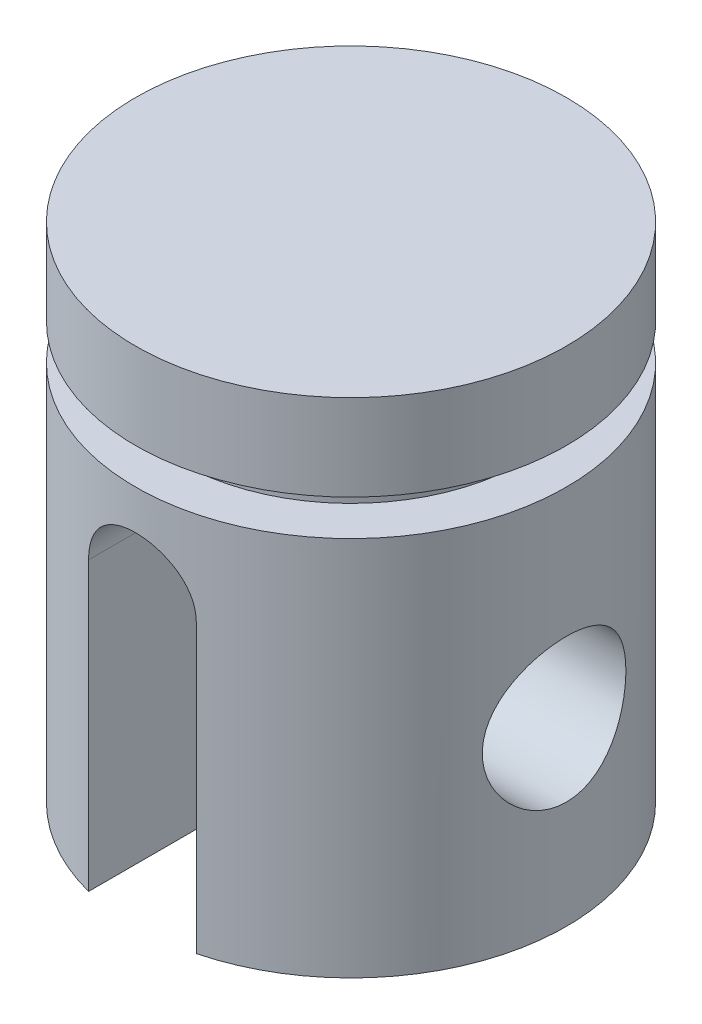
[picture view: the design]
ISO-10303-21;
HEADER;
FILE_DESCRIPTION(('STEP AP214'),'2;1');
FILE_NAME('part.step','',(''),(''),'','','');
FILE_SCHEMA(('AUTOMOTIVE_DESIGN { 1 0 10303 214 1 1 1 1 }'));
ENDSEC;
DATA;
#1=APPLICATION_CONTEXT('core data for automotive mechanical design processes');
#2=APPLICATION_PROTOCOL_DEFINITION('international standard','automotive_design',2000,#1);
#3=PRODUCT_CONTEXT('',#1,'mechanical');
#4=PRODUCT('Part','Part','',(#3));
#5=PRODUCT_RELATED_PRODUCT_CATEGORY('part','',(#4));
#6=PRODUCT_DEFINITION_FORMATION('','',#4);
#7=PRODUCT_DEFINITION_CONTEXT('part definition',#1,'design');
#8=PRODUCT_DEFINITION('design','',#6,#7);
#9=PRODUCT_DEFINITION_SHAPE('','',#8);
#10=(LENGTH_UNIT() NAMED_UNIT(*) SI_UNIT(.MILLI.,.METRE.));
#11=(NAMED_UNIT(*) PLANE_ANGLE_UNIT() SI_UNIT($,.RADIAN.));
#12=(NAMED_UNIT(*) SI_UNIT($,.STERADIAN.) SOLID_ANGLE_UNIT());
#13=UNCERTAINTY_MEASURE_WITH_UNIT(LENGTH_MEASURE(1.E-05),#10,'distance_accuracy_value','');
#14=(GEOMETRIC_REPRESENTATION_CONTEXT(3) GLOBAL_UNCERTAINTY_ASSIGNED_CONTEXT((#13)) GLOBAL_UNIT_ASSIGNED_CONTEXT((#10,
#11,#12)) REPRESENTATION_CONTEXT('',''));
#15=CARTESIAN_POINT('',(0.,0.,0.));
#16=DIRECTION('',(0.,0.,1.));
#17=DIRECTION('',(1.,0.,0.));
#18=AXIS2_PLACEMENT_3D('',#15,#16,#17);
#19=CARTESIAN_POINT('',(30.,0.,0.));
#20=DIRECTION('',(0.,-1.,0.));
#21=DIRECTION('',(0.,0.,-1.));
#22=AXIS2_PLACEMENT_3D('',#19,#20,#21);
#23=PLANE('',#22);
#24=DIRECTION('',(0.,0.,1.));
#25=VECTOR('',#24,1.);
#26=CARTESIAN_POINT('',(-7.5,0.,-30.));
#27=LINE('',#26,#25);
#28=CARTESIAN_POINT('',(-7.5,0.,-29.0473750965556));
#29=VERTEX_POINT('',#28);
#30=CARTESIAN_POINT('',(-7.5,0.,29.0473750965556));
#31=VERTEX_POINT('',#30);
#32=EDGE_CURVE('E110',#29,#31,#27,.T.);
#33=ORIENTED_EDGE('',*,*,#32,.T.);
#34=CARTESIAN_POINT('',(0.,0.,0.));
#35=DIRECTION('',(0.,-1.,0.));
#36=DIRECTION('',(0.,0.,-1.));
#37=AXIS2_PLACEMENT_3D('',#34,#35,#36);
#38=CIRCLE('',#37,30.);
#39=EDGE_CURVE('E117',#31,#29,#38,.T.);
#40=ORIENTED_EDGE('',*,*,#39,.T.);
#41=EDGE_LOOP('',(#33,#40));
#42=FACE_BOUND('',#41,.T.);
#43=ADVANCED_FACE('F40',(#42),#23,.T.);
#44=DIRECTION('',(0.,0.,1.));
#45=VECTOR('',#44,1.);
#46=CARTESIAN_POINT('',(7.5,0.,-30.));
#47=LINE('',#46,#45);
#48=CARTESIAN_POINT('',(7.5,0.,-29.0473750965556));
#49=VERTEX_POINT('',#48);
#50=CARTESIAN_POINT('',(7.5,0.,29.0473750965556));
#51=VERTEX_POINT('',#50);
#52=EDGE_CURVE('E98',#49,#51,#47,.T.);
#53=ORIENTED_EDGE('',*,*,#52,.F.);
#54=EDGE_CURVE('E121',#49,#51,#38,.T.);
#55=ORIENTED_EDGE('',*,*,#54,.T.);
#56=EDGE_LOOP('',(#53,#55));
#57=FACE_BOUND('',#56,.T.);
#58=ADVANCED_FACE('F42',(#57),#23,.T.);
#59=CARTESIAN_POINT('',(0.,70.,0.));
#60=DIRECTION('',(0.,1.,0.));
#61=DIRECTION('',(0.,0.,1.));
#62=AXIS2_PLACEMENT_3D('',#59,#60,#61);
#63=PLANE('',#62);
#64=CARTESIAN_POINT('',(0.,70.,0.));
#65=DIRECTION('',(0.,-1.,0.));
#66=DIRECTION('',(0.,0.,-1.));
#67=AXIS2_PLACEMENT_3D('',#64,#65,#66);
#68=CIRCLE('',#67,30.);
#69=CARTESIAN_POINT('',(0.,70.,-30.));
#70=VERTEX_POINT('',#69);
#71=EDGE_CURVE('E94',#70,#70,#68,.T.);
#72=ORIENTED_EDGE('',*,*,#71,.F.);
#73=EDGE_LOOP('',(#72));
#74=FACE_BOUND('',#73,.T.);
#75=ADVANCED_FACE('F207',(#74),#63,.T.);
#76=CARTESIAN_POINT('',(0.,70.,0.));
#77=DIRECTION('',(0.,-1.,0.));
#78=DIRECTION('',(0.,0.,-1.));
#79=AXIS2_PLACEMENT_3D('',#76,#77,#78);
#80=CYLINDRICAL_SURFACE('',#79,30.);
#81=ORIENTED_EDGE('',*,*,#71,.T.);
#82=EDGE_LOOP('',(#81));
#83=FACE_BOUND('',#82,.T.);
#84=CARTESIAN_POINT('',(0.,58.,0.));
#85=DIRECTION('',(0.,-1.,0.));
#86=DIRECTION('',(0.,0.,-1.));
#87=AXIS2_PLACEMENT_3D('',#84,#85,#86);
#88=CIRCLE('',#87,30.);
#89=CARTESIAN_POINT('',(0.,58.,-30.));
#90=VERTEX_POINT('',#89);
#91=EDGE_CURVE('E134',#90,#90,#88,.T.);
#92=ORIENTED_EDGE('',*,*,#91,.F.);
#93=EDGE_LOOP('',(#92));
#94=FACE_BOUND('',#93,.T.);
#95=ADVANCED_FACE('F235',(#83,#94),#80,.T.);
#96=CARTESIAN_POINT('',(30.,58.,0.));
#97=DIRECTION('',(0.,-1.,0.));
#98=DIRECTION('',(0.,0.,-1.));
#99=AXIS2_PLACEMENT_3D('',#96,#97,#98);
#100=PLANE('',#99);
#101=ORIENTED_EDGE('',*,*,#91,.T.);
#102=EDGE_LOOP('',(#101));
#103=FACE_BOUND('',#102,.T.);
#104=CARTESIAN_POINT('',(0.,58.,0.));
#105=DIRECTION('',(0.,-1.,0.));
#106=DIRECTION('',(0.,0.,-1.));
#107=AXIS2_PLACEMENT_3D('',#104,#105,#106);
#108=CIRCLE('',#107,24.);
#109=CARTESIAN_POINT('',(0.,58.,-24.));
#110=VERTEX_POINT('',#109);
#111=EDGE_CURVE('E130',#110,#110,#108,.T.);
#112=ORIENTED_EDGE('',*,*,#111,.F.);
#113=EDGE_LOOP('',(#112));
#114=FACE_BOUND('',#113,.T.);
#115=ADVANCED_FACE('F228',(#103,#114),#100,.T.);
#116=CARTESIAN_POINT('',(0.,70.,0.));
#117=DIRECTION('',(0.,-1.,0.));
#118=DIRECTION('',(0.,0.,-1.));
#119=AXIS2_PLACEMENT_3D('',#116,#117,#118);
#120=CYLINDRICAL_SURFACE('',#119,24.);
#121=ORIENTED_EDGE('',*,*,#111,.T.);
#122=EDGE_LOOP('',(#121));
#123=FACE_BOUND('',#122,.T.);
#124=CARTESIAN_POINT('',(0.,53.,0.));
#125=DIRECTION('',(0.,-1.,0.));
#126=DIRECTION('',(0.,0.,-1.));
#127=AXIS2_PLACEMENT_3D('',#124,#125,#126);
#128=CIRCLE('',#127,24.);
#129=CARTESIAN_POINT('',(0.,53.,-24.));
#130=VERTEX_POINT('',#129);
#131=EDGE_CURVE('E126',#130,#130,#128,.T.);
#132=ORIENTED_EDGE('',*,*,#131,.F.);
#133=EDGE_LOOP('',(#132));
#134=FACE_BOUND('',#133,.T.);
#135=ADVANCED_FACE('F220',(#123,#134),#120,.T.);
#136=CARTESIAN_POINT('',(24.,53.,0.));
#137=DIRECTION('',(0.,1.,0.));
#138=DIRECTION('',(0.,0.,1.));
#139=AXIS2_PLACEMENT_3D('',#136,#137,#138);
#140=PLANE('',#139);
#141=ORIENTED_EDGE('',*,*,#131,.T.);
#142=EDGE_LOOP('',(#141));
#143=FACE_BOUND('',#142,.T.);
#144=CARTESIAN_POINT('',(0.,53.,0.));
#145=DIRECTION('',(0.,-1.,0.));
#146=DIRECTION('',(0.,0.,-1.));
#147=AXIS2_PLACEMENT_3D('',#144,#145,#146);
#148=CIRCLE('',#147,30.);
#149=CARTESIAN_POINT('',(0.,53.,-30.));
#150=VERTEX_POINT('',#149);
#151=EDGE_CURVE('E122',#150,#150,#148,.T.);
#152=ORIENTED_EDGE('',*,*,#151,.F.);
#153=EDGE_LOOP('',(#152));
#154=FACE_BOUND('',#153,.T.);
#155=ADVANCED_FACE('F213',(#143,#154),#140,.T.);
#156=CARTESIAN_POINT('',(0.,70.,0.));
#157=DIRECTION('',(0.,-1.,0.));
#158=DIRECTION('',(0.,0.,-1.));
#159=AXIS2_PLACEMENT_3D('',#156,#157,#158);
#160=CYLINDRICAL_SURFACE('',#159,30.);
#161=CARTESIAN_POINT('',(-30.,15.,0.));
#162=CARTESIAN_POINT('',(-30.0000000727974,14.9999998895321,0.272817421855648));
#163=CARTESIAN_POINT('',(-29.9962700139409,15.0111733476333,0.545633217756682));
#164=CARTESIAN_POINT('',(-29.9814525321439,15.0557586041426,1.08923625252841));
#165=CARTESIAN_POINT('',(-29.9703651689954,15.0891702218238,1.36002350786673));
#166=CARTESIAN_POINT('',(-29.9411347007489,15.1779177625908,1.89761112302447));
#167=CARTESIAN_POINT('',(-29.922991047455,15.2332553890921,2.16441117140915));
#168=CARTESIAN_POINT('',(-29.8801375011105,15.3653481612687,2.69211184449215));
#169=CARTESIAN_POINT('',(-29.8554275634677,15.4421034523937,2.95301242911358));
#170=CARTESIAN_POINT('',(-29.8001502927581,15.6161973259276,3.46664728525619));
#171=CARTESIAN_POINT('',(-29.769594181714,15.7134965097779,3.71939613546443));
#172=CARTESIAN_POINT('',(-29.7033758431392,15.9280132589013,4.21570540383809));
#173=CARTESIAN_POINT('',(-29.6677117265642,16.0452381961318,4.45926238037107));
#174=CARTESIAN_POINT('',(-29.5921987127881,16.2986867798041,4.93557741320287));
#175=CARTESIAN_POINT('',(-29.5523500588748,16.4349093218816,5.16833609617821));
#176=CARTESIAN_POINT('',(-29.4694667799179,16.7254094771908,5.62171195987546));
#177=CARTESIAN_POINT('',(-29.4264319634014,16.8796881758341,5.84232840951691));
#178=CARTESIAN_POINT('',(-29.3368734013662,17.2103752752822,6.27682953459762));
#179=CARTESIAN_POINT('',(-29.2902826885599,17.3873240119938,6.49028930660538));
#180=CARTESIAN_POINT('',(-29.1960870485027,17.7582003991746,6.90166928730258));
#181=CARTESIAN_POINT('',(-29.1484821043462,17.9521283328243,7.09958923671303));
#182=CARTESIAN_POINT('',(-29.0535150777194,18.355812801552,7.47873453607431));
#183=CARTESIAN_POINT('',(-29.0061530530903,18.5655729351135,7.65995606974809));
#184=CARTESIAN_POINT('',(-28.9129673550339,18.9996166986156,8.00450980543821));
#185=CARTESIAN_POINT('',(-28.8671436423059,19.2238999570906,8.16784246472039));
#186=CARTESIAN_POINT('',(-28.7770145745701,19.692372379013,8.48001162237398));
#187=CARTESIAN_POINT('',(-28.7327920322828,19.9369505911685,8.62828897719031));
#188=CARTESIAN_POINT('',(-28.6486860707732,20.438392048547,8.90356690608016));
#189=CARTESIAN_POINT('',(-28.6088009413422,20.6952503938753,9.0305758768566));
#190=CARTESIAN_POINT('',(-28.534611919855,21.2196006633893,9.26232893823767));
#191=CARTESIAN_POINT('',(-28.5003078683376,21.4870922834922,9.36707366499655));
#192=CARTESIAN_POINT('',(-28.4384115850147,22.0307959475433,9.55334459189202));
#193=CARTESIAN_POINT('',(-28.4108190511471,22.307007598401,9.63487183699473));
#194=CARTESIAN_POINT('',(-28.3640896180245,22.8566360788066,9.77156399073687));
#195=CARTESIAN_POINT('',(-28.3446991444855,23.1298335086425,9.82752458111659));
#196=CARTESIAN_POINT('',(-28.3137046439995,23.680382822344,9.91646893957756));
#197=CARTESIAN_POINT('',(-28.3021004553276,23.957734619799,9.94945318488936));
#198=CARTESIAN_POINT('',(-28.2870721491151,24.5143726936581,9.992100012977));
#199=CARTESIAN_POINT('',(-28.2836458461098,24.7936584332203,10.001768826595));
#200=CARTESIAN_POINT('',(-28.2850842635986,25.3520337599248,9.99770051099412));
#201=CARTESIAN_POINT('',(-28.2899487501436,25.6311233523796,9.98396404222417));
#202=CARTESIAN_POINT('',(-28.307391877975,26.1741814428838,9.93439524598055));
#203=CARTESIAN_POINT('',(-28.319607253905,26.4382573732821,9.89960301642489));
#204=CARTESIAN_POINT('',(-28.3510582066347,26.9623784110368,9.80916853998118));
#205=CARTESIAN_POINT('',(-28.3702935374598,27.222423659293,9.75352702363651));
#206=CARTESIAN_POINT('',(-28.4152063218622,27.7367087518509,9.62189570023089));
#207=CARTESIAN_POINT('',(-28.4408831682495,27.990949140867,9.54590781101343));
#208=CARTESIAN_POINT('',(-28.4979443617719,28.4921119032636,9.37418519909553));
#209=CARTESIAN_POINT('',(-28.529330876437,28.7390314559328,9.27844297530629));
#210=CARTESIAN_POINT('',(-28.5974561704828,29.227762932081,9.0663166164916));
#211=CARTESIAN_POINT('',(-28.6342713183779,29.4694335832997,8.94963170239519));
#212=CARTESIAN_POINT('',(-28.7118622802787,29.9422102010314,8.69749161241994));
#213=CARTESIAN_POINT('',(-28.7526394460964,30.1733125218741,8.56203002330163));
#214=CARTESIAN_POINT('',(-28.8370515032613,30.6235621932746,8.27327503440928));
#215=CARTESIAN_POINT('',(-28.8806865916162,30.8427087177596,8.11998040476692));
#216=CARTESIAN_POINT('',(-28.9696785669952,31.2678135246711,7.79652835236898));
#217=CARTESIAN_POINT('',(-29.0150355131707,31.4737713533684,7.62637034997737));
#218=CARTESIAN_POINT('',(-29.1087179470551,31.8817825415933,7.26085153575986));
#219=CARTESIAN_POINT('',(-29.1570743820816,32.0830648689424,7.06463704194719));
#220=CARTESIAN_POINT('',(-29.2530762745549,32.4684195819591,6.65594240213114));
#221=CARTESIAN_POINT('',(-29.300721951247,32.6524973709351,6.44346740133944));
#222=CARTESIAN_POINT('',(-29.3940440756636,33.002391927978,6.00339730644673));
#223=CARTESIAN_POINT('',(-29.4397195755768,33.1681999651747,5.77579506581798));
#224=CARTESIAN_POINT('',(-29.5278149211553,33.4802271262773,5.30706897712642));
#225=CARTESIAN_POINT('',(-29.5702360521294,33.6264540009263,5.06595053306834));
#226=CARTESIAN_POINT('',(-29.6510879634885,33.8996756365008,4.56913058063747));
#227=CARTESIAN_POINT('',(-29.6894737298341,34.0264594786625,4.31330561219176));
#228=CARTESIAN_POINT('',(-29.7606637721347,34.2579286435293,3.79108523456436));
#229=CARTESIAN_POINT('',(-29.7934679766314,34.3626136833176,3.5246896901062));
#230=CARTESIAN_POINT('',(-29.8525359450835,34.5489114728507,2.98332200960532));
#231=CARTESIAN_POINT('',(-29.8788015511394,34.6305307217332,2.70835231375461));
#232=CARTESIAN_POINT('',(-29.92402797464,34.769943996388,2.15185145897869));
#233=CARTESIAN_POINT('',(-29.9429891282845,34.8277391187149,1.87032060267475));
#234=CARTESIAN_POINT('',(-29.9723879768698,34.9169416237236,1.31523069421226));
#235=CARTESIAN_POINT('',(-29.9831596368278,34.949384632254,1.04185537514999));
#236=CARTESIAN_POINT('',(-29.9972012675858,34.9916207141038,0.493170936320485));
#237=CARTESIAN_POINT('',(-30.0004714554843,35.0014144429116,0.217861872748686));
#238=CARTESIAN_POINT('',(-29.9994188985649,34.9982566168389,-0.332568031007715));
#239=CARTESIAN_POINT('',(-29.9950972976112,34.9853084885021,-0.607688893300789));
#240=CARTESIAN_POINT('',(-29.9789840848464,34.9368007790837,-1.15570622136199));
#241=CARTESIAN_POINT('',(-29.9671925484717,34.9012414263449,-1.4286027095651));
#242=CARTESIAN_POINT('',(-29.9369169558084,34.8092212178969,-1.96222703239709));
#243=CARTESIAN_POINT('',(-29.9186384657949,34.7534012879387,-2.22307746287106));
#244=CARTESIAN_POINT('',(-29.8758162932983,34.6212424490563,-2.7390974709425));
#245=CARTESIAN_POINT('',(-29.8512703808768,34.5448962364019,-2.99426499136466));
#246=CARTESIAN_POINT('',(-29.7965488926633,34.372353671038,-3.49708740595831));
#247=CARTESIAN_POINT('',(-29.7663749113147,34.2761629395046,-3.74474440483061));
#248=CARTESIAN_POINT('',(-29.7011345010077,34.0646297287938,-4.23117712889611));
#249=CARTESIAN_POINT('',(-29.6660661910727,33.949279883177,-4.46994939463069));
#250=CARTESIAN_POINT('',(-29.5909467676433,33.6970680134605,-4.94315066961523));
#251=CARTESIAN_POINT('',(-29.5507901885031,33.5597265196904,-5.17730735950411));
#252=CARTESIAN_POINT('',(-29.4672484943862,33.2667077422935,-5.63338688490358));
#253=CARTESIAN_POINT('',(-29.4238619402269,33.1110222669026,-5.85530418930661));
#254=CARTESIAN_POINT('',(-29.3349700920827,32.7823833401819,-6.28552190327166));
#255=CARTESIAN_POINT('',(-29.2894647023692,32.6094291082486,-6.49382169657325));
#256=CARTESIAN_POINT('',(-29.1974842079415,32.2473266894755,-6.89560723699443));
#257=CARTESIAN_POINT('',(-29.1510090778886,32.058178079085,-7.08909259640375));
#258=CARTESIAN_POINT('',(-29.0561491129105,31.6558052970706,-7.46861368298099));
#259=CARTESIAN_POINT('',(-29.007774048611,31.4418759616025,-7.65390507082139));
#260=CARTESIAN_POINT('',(-28.9126373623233,30.998946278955,-8.00578656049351));
#261=CARTESIAN_POINT('',(-28.865875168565,30.7699513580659,-8.17238333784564));
#262=CARTESIAN_POINT('',(-28.7752794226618,30.2981425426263,-8.48586679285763));
#263=CARTESIAN_POINT('',(-28.7314471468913,30.0553227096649,-8.63274490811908));
#264=CARTESIAN_POINT('',(-28.6480650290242,29.5576069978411,-8.90554413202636));
#265=CARTESIAN_POINT('',(-28.6085133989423,29.3027162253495,-9.03147400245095));
#266=CARTESIAN_POINT('',(-28.5349686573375,28.7829217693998,-9.26121465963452));
#267=CARTESIAN_POINT('',(-28.5009658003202,28.5180366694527,-9.3650643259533));
#268=CARTESIAN_POINT('',(-28.4395326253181,27.9796830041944,-9.54999948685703));
#269=CARTESIAN_POINT('',(-28.4121023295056,27.7062144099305,-9.63108490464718));
#270=CARTESIAN_POINT('',(-28.364744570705,27.1528332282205,-9.76967941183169));
#271=CARTESIAN_POINT('',(-28.3448142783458,26.8729231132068,-9.82719739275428));
#272=CARTESIAN_POINT('',(-28.3131339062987,26.3087576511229,-9.91810350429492));
#273=CARTESIAN_POINT('',(-28.301383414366,26.0245025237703,-9.95149285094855));
#274=CARTESIAN_POINT('',(-28.2868595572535,25.4686336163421,-9.99269827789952));
#275=CARTESIAN_POINT('',(-28.2836556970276,25.1971213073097,-10.0017409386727));
#276=CARTESIAN_POINT('',(-28.2850819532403,24.6542875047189,-9.99770707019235));
#277=CARTESIAN_POINT('',(-28.2897117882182,24.3829660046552,-9.98463133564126));
#278=CARTESIAN_POINT('',(-28.3066557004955,23.8425445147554,-9.9364928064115));
#279=CARTESIAN_POINT('',(-28.3189692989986,23.573444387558,-9.90143138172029));
#280=CARTESIAN_POINT('',(-28.3508886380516,23.0394036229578,-9.80966197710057));
#281=CARTESIAN_POINT('',(-28.3704944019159,22.7744629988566,-9.7529539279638));
#282=CARTESIAN_POINT('',(-28.4159458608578,22.2556454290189,-9.61971250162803));
#283=CARTESIAN_POINT('',(-28.441664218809,22.0016536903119,-9.54358162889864));
#284=CARTESIAN_POINT('',(-28.498791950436,21.5009969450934,-9.3716093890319));
#285=CARTESIAN_POINT('',(-28.5302033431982,21.2543345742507,-9.27576102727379));
#286=CARTESIAN_POINT('',(-28.597830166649,20.76993896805,-9.06511647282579));
#287=CARTESIAN_POINT('',(-28.6340454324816,20.5322054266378,-8.9503209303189));
#288=CARTESIAN_POINT('',(-28.7103060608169,20.0670154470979,-8.7025924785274));
#289=CARTESIAN_POINT('',(-28.7503516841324,19.839559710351,-8.56965833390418));
#290=CARTESIAN_POINT('',(-28.8350396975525,19.3865184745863,-8.28034879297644));
#291=CARTESIAN_POINT('',(-28.8798064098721,19.1614474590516,-8.12320375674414));
#292=CARTESIAN_POINT('',(-28.9711505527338,18.725203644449,-7.791153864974));
#293=CARTESIAN_POINT('',(-29.0177280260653,18.5140311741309,-7.61624858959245));
#294=CARTESIAN_POINT('',(-29.1114649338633,18.1067657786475,-7.24971676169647));
#295=CARTESIAN_POINT('',(-29.1586245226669,17.9106769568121,-7.0580856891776));
#296=CARTESIAN_POINT('',(-29.2522781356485,17.5348203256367,-6.65929199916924));
#297=CARTESIAN_POINT('',(-29.2987721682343,17.3550523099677,-6.45212957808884));
#298=CARTESIAN_POINT('',(-29.3916811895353,17.0062342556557,-6.01505765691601));
#299=CARTESIAN_POINT('',(-29.4380213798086,16.8378823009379,-5.78457436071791));
#300=CARTESIAN_POINT('',(-29.5273677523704,16.5212909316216,-5.30969823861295));
#301=CARTESIAN_POINT('',(-29.5703751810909,16.3730439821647,-5.06531067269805));
#302=CARTESIAN_POINT('',(-29.6518631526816,16.0977371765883,-4.56414864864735));
#303=CARTESIAN_POINT('',(-29.6903436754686,15.9706774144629,-4.30737413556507));
#304=CARTESIAN_POINT('',(-29.7616741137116,15.7388217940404,-3.78321180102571));
#305=CARTESIAN_POINT('',(-29.7945243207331,15.6340247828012,-3.51582453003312));
#306=CARTESIAN_POINT('',(-29.8523172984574,15.4518077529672,-2.98451649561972));
#307=CARTESIAN_POINT('',(-29.877547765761,15.3733738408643,-2.72097451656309));
#308=CARTESIAN_POINT('',(-29.9213145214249,15.238384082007,-2.1878001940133));
#309=CARTESIAN_POINT('',(-29.9398510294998,15.181827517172,-1.91816805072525));
#310=CARTESIAN_POINT('',(-29.9697157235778,15.0911304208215,-1.37482625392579));
#311=CARTESIAN_POINT('',(-29.9810455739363,15.0569847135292,-1.10111755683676));
#312=CARTESIAN_POINT('',(-29.9961876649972,15.0114195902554,-0.551605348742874));
#313=CARTESIAN_POINT('',(-29.9999999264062,15.0000001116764,-0.275801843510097));
#314=CARTESIAN_POINT('',(-30.,15.,0.));
#315=B_SPLINE_CURVE_WITH_KNOTS('',3,(#161,#162,#163,#164,#165,#166,#167,#168,#169,#170,#171,
#172,#173,#174,#175,#176,#177,#178,#179,#180,#181,#182,#183,#184,#185,#186,#187,#188,#189,#190,
#191,#192,#193,#194,#195,#196,#197,#198,#199,#200,#201,#202,#203,#204,#205,#206,#207,#208,#209,
#210,#211,#212,#213,#214,#215,#216,#217,#218,#219,#220,#221,#222,#223,#224,#225,#226,#227,#228,
#229,#230,#231,#232,#233,#234,#235,#236,#237,#238,#239,#240,#241,#242,#243,#244,#245,#246,#247,
#248,#249,#250,#251,#252,#253,#254,#255,#256,#257,#258,#259,#260,#261,#262,#263,#264,#265,#266,
#267,#268,#269,#270,#271,#272,#273,#274,#275,#276,#277,#278,#279,#280,#281,#282,#283,#284,#285,
#286,#287,#288,#289,#290,#291,#292,#293,#294,#295,#296,#297,#298,#299,#300,#301,#302,#303,#304,
#305,#306,#307,#308,#309,#310,#311,#312,#313,#314),.UNSPECIFIED.,.T.,.F.,(4,2,2,2,2,2,2,2,2,2,2,
2,2,2,2,2,2,2,2,2,2,2,2,2,2,2,2,2,2,2,2,2,2,2,2,2,2,2,2,2,2,2,2,2,2,2,2,2,2,2,2,2,2,2,2,2,2,2,2,
2,2,2,2,2,2,2,2,2,2,2,2,2,2,2,2,2,4),(0.,0.818196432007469,1.6363862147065,2.45463957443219,
3.2728984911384,4.08960219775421,4.90660872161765,5.72356777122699,6.54057595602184,
7.38307938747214,8.22559687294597,9.06830643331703,9.91099444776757,10.7781693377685,
11.645001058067,12.5118080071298,13.3785759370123,14.2161395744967,15.0536858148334,
15.8910082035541,16.7283069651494,17.5272827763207,18.3262305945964,19.1251031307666,
19.9242795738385,20.7360167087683,21.5480317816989,22.3601028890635,23.1722019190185,
24.0268844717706,24.881297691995,25.7361174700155,26.590597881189,27.453776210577,
28.3169655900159,29.1799115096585,30.0428177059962,30.8683037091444,31.6937658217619,
32.5191035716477,33.3444329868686,34.1456526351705,34.9471577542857,35.7484361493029,
36.5500233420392,37.3723552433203,38.1950557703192,39.0177935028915,39.8405527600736,
40.7009055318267,41.5609501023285,42.4213669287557,43.2814229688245,44.1399518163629,
44.998483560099,45.8566910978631,46.7148553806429,47.5288973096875,48.3429099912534,
49.1568719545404,49.9708365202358,50.7691377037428,51.5677225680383,52.3662800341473,
53.1648919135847,53.9983437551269,54.831815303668,55.665512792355,56.4991997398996,
57.3656243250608,58.2317232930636,59.0978261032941,59.9638840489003,60.7912515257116,
61.618591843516,62.4457410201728,63.2728879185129),.UNSPECIFIED.);
#316=CARTESIAN_POINT('',(-30.,15.,0.));
#317=VERTEX_POINT('',#316);
#318=EDGE_CURVE('E113',#317,#317,#315,.T.);
#319=ORIENTED_EDGE('',*,*,#318,.F.);
#320=EDGE_LOOP('',(#319));
#321=FACE_BOUND('',#320,.T.);
#322=CARTESIAN_POINT('',(28.2842712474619,25.,-10.));
#323=CARTESIAN_POINT('',(28.2842711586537,25.2723418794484,-10.0000001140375));
#324=CARTESIAN_POINT('',(28.2882153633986,25.5446821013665,-9.98886524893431));
#325=CARTESIAN_POINT('',(28.303863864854,26.0873201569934,-9.94443775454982));
#326=CARTESIAN_POINT('',(28.3155681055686,26.3576180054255,-9.91114528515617));
#327=CARTESIAN_POINT('',(28.3463631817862,26.8942210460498,-9.82272262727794));
#328=CARTESIAN_POINT('',(28.3654549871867,27.1605257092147,-9.76758957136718));
#329=CARTESIAN_POINT('',(28.4104260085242,27.6872225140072,-9.63600126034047));
#330=CARTESIAN_POINT('',(28.4363052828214,27.9476146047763,-9.55954582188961));
#331=CARTESIAN_POINT('',(28.4939998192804,28.4601649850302,-9.38617562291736));
#332=CARTESIAN_POINT('',(28.5258019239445,28.7123400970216,-9.28930615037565));
#333=CARTESIAN_POINT('',(28.594462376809,29.2075458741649,-9.07575323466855));
#334=CARTESIAN_POINT('',(28.6313226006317,29.4505731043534,-8.95906243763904));
#335=CARTESIAN_POINT('',(28.7090513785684,29.9259128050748,-8.70676649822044));
#336=CARTESIAN_POINT('',(28.749919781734,30.1582256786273,-8.57116206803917));
#337=CARTESIAN_POINT('',(28.8345602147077,30.610819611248,-8.28195822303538));
#338=CARTESIAN_POINT('',(28.8783324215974,30.8310999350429,-8.12835771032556));
#339=CARTESIAN_POINT('',(28.969218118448,31.2659723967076,-7.79837866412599));
#340=CARTESIAN_POINT('',(29.0163950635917,31.4800846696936,-7.62138490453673));
#341=CARTESIAN_POINT('',(29.1113399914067,31.8927827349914,-7.25028001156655));
#342=CARTESIAN_POINT('',(29.1591079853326,32.0913682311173,-7.05616855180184));
#343=CARTESIAN_POINT('',(29.2539610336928,32.4718262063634,-6.65198113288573));
#344=CARTESIAN_POINT('',(29.3010459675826,32.6536957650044,-6.44190239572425));
#345=CARTESIAN_POINT('',(29.3932703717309,32.9995074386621,-6.00708268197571));
#346=CARTESIAN_POINT('',(29.4384099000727,33.1634500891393,-5.78234214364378));
#347=CARTESIAN_POINT('',(29.5266957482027,33.4763726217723,-5.31343875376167));
#348=CARTESIAN_POINT('',(29.5697580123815,33.6248433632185,-5.06891983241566));
#349=CARTESIAN_POINT('',(29.6513369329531,33.9005121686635,-4.56756881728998));
#350=CARTESIAN_POINT('',(29.6898553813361,34.0277186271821,-4.31074163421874));
#351=CARTESIAN_POINT('',(29.7612633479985,34.2598596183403,-3.78644812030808));
#352=CARTESIAN_POINT('',(29.7941528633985,34.3647941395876,-3.51898178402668));
#353=CARTESIAN_POINT('',(29.8533415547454,34.5514314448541,-2.9753549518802));
#354=CARTESIAN_POINT('',(29.8796410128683,34.6331352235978,-2.69919482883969));
#355=CARTESIAN_POINT('',(29.9240820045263,34.7700936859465,-2.15001211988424));
#356=CARTESIAN_POINT('',(29.9424755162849,34.8261696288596,-1.87721461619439));
#357=CARTESIAN_POINT('',(29.9718782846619,34.9154055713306,-1.32750200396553));
#358=CARTESIAN_POINT('',(29.982887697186,34.9485660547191,-1.05058698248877));
#359=CARTESIAN_POINT('',(29.997206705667,34.9916376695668,-0.494817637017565));
#360=CARTESIAN_POINT('',(30.0005180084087,35.0015539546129,-0.215963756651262));
#361=CARTESIAN_POINT('',(29.9993505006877,34.9980515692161,0.341577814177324));
#362=CARTESIAN_POINT('',(29.9948718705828,34.9846334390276,0.620265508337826));
#363=CARTESIAN_POINT('',(29.9785811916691,34.9355842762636,1.16440400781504));
#364=CARTESIAN_POINT('',(29.9670641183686,34.9008464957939,1.42994475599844));
#365=CARTESIAN_POINT('',(29.9372641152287,34.8102808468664,1.95700946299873));
#366=CARTESIAN_POINT('',(29.9189813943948,34.754453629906,2.21853354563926));
#367=CARTESIAN_POINT('',(29.8761277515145,34.6222095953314,2.73574967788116));
#368=CARTESIAN_POINT('',(29.8515577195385,34.5457956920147,2.99144254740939));
#369=CARTESIAN_POINT('',(29.7967458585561,34.3729812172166,3.49545812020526));
#370=CARTESIAN_POINT('',(29.7665018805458,34.2765730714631,3.74377798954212));
#371=CARTESIAN_POINT('',(29.7006905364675,34.0631917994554,4.2345072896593));
#372=CARTESIAN_POINT('',(29.6650602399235,33.9459722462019,4.47680106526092));
#373=CARTESIAN_POINT('',(29.5896554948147,33.6926596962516,4.95074703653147));
#374=CARTESIAN_POINT('',(29.5498795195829,33.5565597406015,5.18239526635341));
#375=CARTESIAN_POINT('',(29.467185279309,33.2664583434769,5.63361428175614));
#376=CARTESIAN_POINT('',(29.4242668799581,33.1124561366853,5.85318455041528));
#377=CARTESIAN_POINT('',(29.3363500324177,32.7875470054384,6.27899992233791));
#378=CARTESIAN_POINT('',(29.2913515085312,32.6166394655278,6.4852445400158));
#379=CARTESIAN_POINT('',(29.198230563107,32.2504812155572,6.89268066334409));
#380=CARTESIAN_POINT('',(29.150061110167,32.0544610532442,7.09317055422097));
#381=CARTESIAN_POINT('',(29.0539933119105,31.6463400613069,7.47693750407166));
#382=CARTESIAN_POINT('',(29.0060948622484,31.4342459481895,7.66022168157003));
#383=CARTESIAN_POINT('',(28.911847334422,30.9950753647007,8.00859996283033));
#384=CARTESIAN_POINT('',(28.8654991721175,30.7679902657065,8.17368344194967));
#385=CARTESIAN_POINT('',(28.775718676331,30.300433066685,8.48434780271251));
#386=CARTESIAN_POINT('',(28.7322851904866,30.0599663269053,8.62993641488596));
#387=CARTESIAN_POINT('',(28.64898095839,29.5634279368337,8.90261331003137));
#388=CARTESIAN_POINT('',(28.6091721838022,29.3071784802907,9.02939717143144));
#389=CARTESIAN_POINT('',(28.5351208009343,28.7841885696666,9.26075808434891));
#390=CARTESIAN_POINT('',(28.5008758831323,28.5174525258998,9.36534435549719));
#391=CARTESIAN_POINT('',(28.439058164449,27.9753195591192,9.55141833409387));
#392=CARTESIAN_POINT('',(28.4114845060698,27.699923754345,9.63290901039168));
#393=CARTESIAN_POINT('',(28.3639441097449,27.1425234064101,9.77200545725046));
#394=CARTESIAN_POINT('',(28.3439769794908,26.8605192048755,9.82961245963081));
#395=CARTESIAN_POINT('',(28.3130630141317,26.3049734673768,9.9182943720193));
#396=CARTESIAN_POINT('',(28.3017497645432,26.031624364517,9.95044933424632));
#397=CARTESIAN_POINT('',(28.287066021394,25.4829950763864,9.99211639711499));
#398=CARTESIAN_POINT('',(28.2836952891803,25.2077149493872,10.0016291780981));
#399=CARTESIAN_POINT('',(28.2850080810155,24.6573740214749,9.9979157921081));
#400=CARTESIAN_POINT('',(28.2896902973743,24.3823131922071,9.98469331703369));
#401=CARTESIAN_POINT('',(28.3069515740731,23.8344674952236,9.9356512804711));
#402=CARTESIAN_POINT('',(28.3195305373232,23.5616825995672,9.89983199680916));
#403=CARTESIAN_POINT('',(28.3516074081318,23.0298042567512,9.80758102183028));
#404=CARTESIAN_POINT('',(28.3708507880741,22.7705637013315,9.75190561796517));
#405=CARTESIAN_POINT('',(28.4157468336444,22.2577495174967,9.62029948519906));
#406=CARTESIAN_POINT('',(28.4414017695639,22.0041779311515,9.54436158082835));
#407=CARTESIAN_POINT('',(28.4983692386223,21.5044799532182,9.37289185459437));
#408=CARTESIAN_POINT('',(28.529680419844,21.2583517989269,9.27736471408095));
#409=CARTESIAN_POINT('',(28.597103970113,20.7748737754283,9.06740307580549));
#410=CARTESIAN_POINT('',(28.6332181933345,20.5375273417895,8.95296127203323));
#411=CARTESIAN_POINT('',(28.710459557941,20.0658014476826,8.70214104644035));
#412=CARTESIAN_POINT('',(28.7517082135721,19.8317473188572,8.5651881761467));
#413=CARTESIAN_POINT('',(28.8371535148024,19.3758018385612,8.2729531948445));
#414=CARTESIAN_POINT('',(28.8813514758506,19.1539159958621,8.11766288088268));
#415=CARTESIAN_POINT('',(28.9715031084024,18.7236756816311,7.78979500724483));
#416=CARTESIAN_POINT('',(29.0174568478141,18.5153217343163,7.61721677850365));
#417=CARTESIAN_POINT('',(29.1099265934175,18.1133393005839,7.25582239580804));
#418=CARTESIAN_POINT('',(29.1564426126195,17.9197111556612,7.06700586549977));
#419=CARTESIAN_POINT('',(29.2510891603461,17.5393176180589,6.66472112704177));
#420=CARTESIAN_POINT('',(29.2991889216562,17.3533374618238,6.45050221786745));
#421=CARTESIAN_POINT('',(29.3933527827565,17.0001149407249,6.00684695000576));
#422=CARTESIAN_POINT('',(29.4394176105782,16.8328658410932,5.77741610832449));
#423=CARTESIAN_POINT('',(29.5282725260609,16.5181558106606,5.30461980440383));
#424=CARTESIAN_POINT('',(29.5710613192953,16.3707026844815,5.06124889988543));
#425=CARTESIAN_POINT('',(29.6521306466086,16.0968569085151,4.56234364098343));
#426=CARTESIAN_POINT('',(29.6904130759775,15.970455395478,4.30681446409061));
#427=CARTESIAN_POINT('',(29.7611781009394,15.7404305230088,3.78690590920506));
#428=CARTESIAN_POINT('',(29.7936962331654,15.6366666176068,3.52259360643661));
#429=CARTESIAN_POINT('',(29.8523040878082,15.4518195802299,2.98545108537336));
#430=CARTESIAN_POINT('',(29.8783938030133,15.3707364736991,2.71262085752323));
#431=CARTESIAN_POINT('',(29.9233798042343,15.2320439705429,2.16055813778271));
#432=CARTESIAN_POINT('',(29.942278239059,15.1744275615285,1.88132758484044));
#433=CARTESIAN_POINT('',(29.9723335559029,15.0832142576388,1.31856201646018));
#434=CARTESIAN_POINT('',(29.983490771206,15.0496163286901,1.03502718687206));
#435=CARTESIAN_POINT('',(29.9973972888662,15.0077927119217,0.47931926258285));
#436=CARTESIAN_POINT('',(30.0005173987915,14.9984478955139,0.207239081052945));
#437=CARTESIAN_POINT('',(29.9993428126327,15.0019714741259,-0.336755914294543));
#438=CARTESIAN_POINT('',(29.9950483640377,15.0148391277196,-0.608670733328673));
#439=CARTESIAN_POINT('',(29.9791626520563,15.0626613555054,-1.15030993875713));
#440=CARTESIAN_POINT('',(29.9675719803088,15.0976141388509,-1.42003450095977));
#441=CARTESIAN_POINT('',(29.9374086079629,15.1892760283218,-1.95536187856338));
#442=CARTESIAN_POINT('',(29.9188358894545,15.2459851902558,-2.22096468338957));
#443=CARTESIAN_POINT('',(29.8755584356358,15.3795575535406,-2.74194020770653));
#444=CARTESIAN_POINT('',(29.8509573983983,15.4560810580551,-2.99740882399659));
#445=CARTESIAN_POINT('',(29.7960968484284,15.629081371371,-3.50096941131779));
#446=CARTESIAN_POINT('',(29.7658353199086,15.7255652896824,-3.74905871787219));
#447=CARTESIAN_POINT('',(29.7004207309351,15.9377063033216,-4.23620216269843));
#448=CARTESIAN_POINT('',(29.6652680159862,16.0533620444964,-4.47525693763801));
#449=CARTESIAN_POINT('',(29.5909339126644,16.3030139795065,-4.94294527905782));
#450=CARTESIAN_POINT('',(29.551752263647,16.4370113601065,-5.1715781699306));
#451=CARTESIAN_POINT('',(29.4688081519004,16.7277108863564,-5.62534353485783));
#452=CARTESIAN_POINT('',(29.4249299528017,16.8850687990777,-5.85003487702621));
#453=CARTESIAN_POINT('',(29.3350010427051,17.2174631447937,-6.28547126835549));
#454=CARTESIAN_POINT('',(29.2889502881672,17.3924999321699,-6.49621603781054));
#455=CARTESIAN_POINT('',(29.1958514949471,17.7591991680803,-6.90258840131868));
#456=CARTESIAN_POINT('',(29.148803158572,17.9508666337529,-7.09821139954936));
#457=CARTESIAN_POINT('',(29.0549477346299,18.3496217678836,-7.47310912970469));
#458=CARTESIAN_POINT('',(29.0081406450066,18.5567093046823,-7.65238400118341));
#459=CARTESIAN_POINT('',(28.914186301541,18.9935507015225,-8.00022249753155));
#460=CARTESIAN_POINT('',(28.8670984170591,19.2238763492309,-8.16808498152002));
#461=CARTESIAN_POINT('',(28.7759175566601,19.6983400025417,-8.48372301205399));
#462=CARTESIAN_POINT('',(28.7318234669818,19.942472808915,-8.63150604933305));
#463=CARTESIAN_POINT('',(28.6479466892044,20.4430577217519,-8.90593894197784));
#464=CARTESIAN_POINT('',(28.6081640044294,20.699509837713,-9.03258878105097));
#465=CARTESIAN_POINT('',(28.5341661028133,21.2229973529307,-9.26369799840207));
#466=CARTESIAN_POINT('',(28.4999505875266,21.4900321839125,-9.36815856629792));
#467=CARTESIAN_POINT('',(28.439603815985,22.0205145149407,-9.54974733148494));
#468=CARTESIAN_POINT('',(28.4131771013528,22.2835787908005,-9.62789736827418));
#469=CARTESIAN_POINT('',(28.3672416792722,22.8158133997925,-9.76241059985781));
#470=CARTESIAN_POINT('',(28.3477327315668,23.0849835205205,-9.8187745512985));
#471=CARTESIAN_POINT('',(28.3162626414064,23.6274076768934,-9.90916574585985));
#472=CARTESIAN_POINT('',(28.304299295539,23.9006604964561,-9.94319950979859));
#473=CARTESIAN_POINT('',(28.2883036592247,24.4492761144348,-9.98861653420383));
#474=CARTESIAN_POINT('',(28.2842713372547,24.72463890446,-9.99999988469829));
#475=CARTESIAN_POINT('',(28.2842712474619,25.,-10.));
#476=B_SPLINE_CURVE_WITH_KNOTS('',3,(#322,#323,#324,#325,#326,#327,#328,#329,#330,#331,#332,
#333,#334,#335,#336,#337,#338,#339,#340,#341,#342,#343,#344,#345,#346,#347,#348,#349,#350,#351,
#352,#353,#354,#355,#356,#357,#358,#359,#360,#361,#362,#363,#364,#365,#366,#367,#368,#369,#370,
#371,#372,#373,#374,#375,#376,#377,#378,#379,#380,#381,#382,#383,#384,#385,#386,#387,#388,#389,
#390,#391,#392,#393,#394,#395,#396,#397,#398,#399,#400,#401,#402,#403,#404,#405,#406,#407,#408,
#409,#410,#411,#412,#413,#414,#415,#416,#417,#418,#419,#420,#421,#422,#423,#424,#425,#426,#427,
#428,#429,#430,#431,#432,#433,#434,#435,#436,#437,#438,#439,#440,#441,#442,#443,#444,#445,#446,
#447,#448,#449,#450,#451,#452,#453,#454,#455,#456,#457,#458,#459,#460,#461,#462,#463,#464,#465,
#466,#467,#468,#469,#470,#471,#472,#473,#474,#475),.UNSPECIFIED.,.T.,.F.,(4,2,2,2,2,2,2,2,2,2,2,
2,2,2,2,2,2,2,2,2,2,2,2,2,2,2,2,2,2,2,2,2,2,2,2,2,2,2,2,2,2,2,2,2,2,2,2,2,2,2,2,2,2,2,2,2,2,2,2,
2,2,2,2,2,2,2,2,2,2,2,2,2,2,2,2,2,4),(0.,0.81676805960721,1.6335302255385,2.45039965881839,
3.26727611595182,4.08235908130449,4.89774511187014,5.71310044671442,6.52850554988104,
7.37286999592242,8.21725054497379,9.06177833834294,9.90628089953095,10.7730733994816,
11.6395229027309,12.5059728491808,13.3723856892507,14.208656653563,15.0449099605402,
15.8809778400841,16.7170263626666,17.5202339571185,18.3234167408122,19.1264858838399,
19.9298598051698,20.74347212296,21.5573851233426,22.3713329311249,23.1853103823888,
24.0378278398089,24.889991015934,25.7426490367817,26.5949679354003,27.459853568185,
28.3243792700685,29.1887937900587,30.0531637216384,30.8785251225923,31.7038617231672,
32.5290643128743,33.3542567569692,34.1508897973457,34.9478053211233,35.7445306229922,
36.5415643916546,37.3635426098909,38.1858899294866,39.0082690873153,39.8306673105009,
40.692853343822,41.5547283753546,42.4169422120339,43.2787921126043,44.1351284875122,
44.9914658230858,45.8475470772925,46.7035914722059,47.5193689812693,48.3351192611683,
49.1508034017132,49.9664896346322,50.7690241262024,51.5718449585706,52.3746091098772,
53.1774252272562,54.009891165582,54.8423737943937,55.6751084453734,56.507835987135,
57.3734004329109,58.2386410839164,59.1038824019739,59.9690773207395,60.7951734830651,
61.621240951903,62.44706708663,63.2728899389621),.UNSPECIFIED.);
#477=CARTESIAN_POINT('',(28.2842712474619,25.,-10.));
#478=VERTEX_POINT('',#477);
#479=EDGE_CURVE('E174',#478,#478,#476,.T.);
#480=ORIENTED_EDGE('',*,*,#479,.F.);
#481=EDGE_LOOP('',(#480));
#482=FACE_BOUND('',#481,.T.);
#483=DIRECTION('',(0.,-1.,0.));
#484=VECTOR('',#483,1.);
#485=CARTESIAN_POINT('',(-7.5,70.,-29.0473750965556));
#486=LINE('',#485,#484);
#487=CARTESIAN_POINT('',(-7.5,40.,-29.0473750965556));
#488=VERTEX_POINT('',#487);
#489=EDGE_CURVE('E11',#29,#488,#486,.F.);
#490=ORIENTED_EDGE('',*,*,#489,.F.);
#491=ORIENTED_EDGE('',*,*,#39,.F.);
#492=DIRECTION('',(0.,-1.,0.));
#493=VECTOR('',#492,1.);
#494=CARTESIAN_POINT('',(-7.5,70.,29.0473750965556));
#495=LINE('',#494,#493);
#496=CARTESIAN_POINT('',(-7.5,40.,29.0473750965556));
#497=VERTEX_POINT('',#496);
#498=EDGE_CURVE('E65',#497,#31,#495,.T.);
#499=ORIENTED_EDGE('',*,*,#498,.F.);
#500=CARTESIAN_POINT('',(7.49999999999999,40.,29.0473750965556));
#501=CARTESIAN_POINT('',(7.50002630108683,40.2074094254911,29.0473511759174));
#502=CARTESIAN_POINT('',(7.49139743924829,40.4148104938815,29.0495957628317));
#503=CARTESIAN_POINT('',(7.45702283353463,40.8280617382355,29.058447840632));
#504=CARTESIAN_POINT('',(7.43127996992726,41.0339121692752,29.0650545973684));
#505=CARTESIAN_POINT('',(7.36293825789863,41.4421950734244,29.0824398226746));
#506=CARTESIAN_POINT('',(7.32037280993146,41.6446334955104,29.0932100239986));
#507=CARTESIAN_POINT('',(7.21874728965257,42.0450801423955,29.1185927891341));
#508=CARTESIAN_POINT('',(7.15968699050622,42.24308830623,29.1332054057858));
#509=CARTESIAN_POINT('',(7.02556473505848,42.6332457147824,29.1658394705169));
#510=CARTESIAN_POINT('',(6.95050780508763,42.8253967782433,29.1838598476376));
#511=CARTESIAN_POINT('',(6.78492631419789,43.2026916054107,29.2227994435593));
#512=CARTESIAN_POINT('',(6.69439601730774,43.3878327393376,29.2437197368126));
#513=CARTESIAN_POINT('',(6.49856054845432,43.7498067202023,29.2878606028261));
#514=CARTESIAN_POINT('',(6.3932572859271,43.9266406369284,29.311080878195));
#515=CARTESIAN_POINT('',(6.16855831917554,44.2709680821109,29.3591908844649));
#516=CARTESIAN_POINT('',(6.04915733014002,44.4384580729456,29.3840812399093));
#517=CARTESIAN_POINT('',(5.79464941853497,44.7661199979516,29.4353394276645));
#518=CARTESIAN_POINT('',(5.65928334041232,44.9260876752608,29.4617265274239));
#519=CARTESIAN_POINT('',(5.37562488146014,45.2341682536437,29.5148010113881));
#520=CARTESIAN_POINT('',(5.22732801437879,45.3822770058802,29.5414884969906));
#521=CARTESIAN_POINT('',(4.91882000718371,45.6656042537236,29.5944200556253));
#522=CARTESIAN_POINT('',(4.75860893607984,45.8008228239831,29.6206641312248));
#523=CARTESIAN_POINT('',(4.42731474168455,46.0574572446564,29.6719897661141));
#524=CARTESIAN_POINT('',(4.25623168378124,46.1788731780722,29.6970713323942));
#525=CARTESIAN_POINT('',(3.90181138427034,46.4086739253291,29.7457275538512));
#526=CARTESIAN_POINT('',(3.71833478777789,46.5168495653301,29.7692758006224));
#527=CARTESIAN_POINT('',(3.34266809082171,46.7172820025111,29.8137942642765));
#528=CARTESIAN_POINT('',(3.15048118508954,46.8095445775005,29.8347654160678));
#529=CARTESIAN_POINT('',(2.75863317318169,46.9774916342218,29.8735452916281));
#530=CARTESIAN_POINT('',(2.55897043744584,47.053172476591,29.8913533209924));
#531=CARTESIAN_POINT('',(2.15373172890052,47.1872782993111,29.9232806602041));
#532=CARTESIAN_POINT('',(1.94815822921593,47.2457103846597,29.9374014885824));
#533=CARTESIAN_POINT('',(1.53667744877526,47.3438728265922,29.9613124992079));
#534=CARTESIAN_POINT('',(1.33085796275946,47.3839517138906,29.9711831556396));
#535=CARTESIAN_POINT('',(0.916507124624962,47.4467377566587,29.986713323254));
#536=CARTESIAN_POINT('',(0.707976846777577,47.4694515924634,29.9923744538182));
#537=CARTESIAN_POINT('',(0.289657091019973,47.4973358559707,29.9993310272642));
#538=CARTESIAN_POINT('',(0.0798675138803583,47.5025048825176,30.0006261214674));
#539=CARTESIAN_POINT('',(-0.339386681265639,47.4952499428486,29.9988126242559));
#540=CARTESIAN_POINT('',(-0.548851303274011,47.4828261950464,29.9957040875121));
#541=CARTESIAN_POINT('',(-0.961217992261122,47.4409706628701,29.9852905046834));
#542=CARTESIAN_POINT('',(-1.16416193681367,47.4119262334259,29.9780810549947));
#543=CARTESIAN_POINT('',(-1.56688998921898,47.3373569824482,29.9597313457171));
#544=CARTESIAN_POINT('',(-1.76667298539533,47.2918264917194,29.9485897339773));
#545=CARTESIAN_POINT('',(-2.16155863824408,47.184671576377,29.9226804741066));
#546=CARTESIAN_POINT('',(-2.3566628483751,47.1230525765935,29.9079140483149));
#547=CARTESIAN_POINT('',(-2.74101865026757,46.9841669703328,29.8751407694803));
#548=CARTESIAN_POINT('',(-2.9302680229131,46.9068945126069,29.857132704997));
#549=CARTESIAN_POINT('',(-3.30321049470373,46.7365562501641,29.8181867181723));
#550=CARTESIAN_POINT('',(-3.48684111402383,46.6433591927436,29.7972247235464));
#551=CARTESIAN_POINT('',(-3.84567797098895,46.4422880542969,29.7530411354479));
#552=CARTESIAN_POINT('',(-4.02088127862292,46.3344089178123,29.7298187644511));
#553=CARTESIAN_POINT('',(-4.36167586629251,46.1047524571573,29.6817351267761));
#554=CARTESIAN_POINT('',(-4.52726762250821,45.9829758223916,29.6568739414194));
#555=CARTESIAN_POINT('',(-4.84781396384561,45.7263301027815,29.6061655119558));
#556=CARTESIAN_POINT('',(-5.00276833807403,45.5914607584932,29.580318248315));
#557=CARTESIAN_POINT('',(-5.30512497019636,45.3056657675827,29.5276114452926));
#558=CARTESIAN_POINT('',(-5.45220775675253,45.1544034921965,29.5007434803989));
#559=CARTESIAN_POINT('',(-5.73309923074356,44.8400403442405,29.4474448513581));
#560=CARTESIAN_POINT('',(-5.86691229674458,44.676943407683,29.4210140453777));
#561=CARTESIAN_POINT('',(-6.12049046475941,44.3398284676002,29.3693097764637));
#562=CARTESIAN_POINT('',(-6.24024642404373,44.1658034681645,29.3440370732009));
#563=CARTESIAN_POINT('',(-6.46471718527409,43.8081478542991,29.2954027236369));
#564=CARTESIAN_POINT('',(-6.56943777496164,43.624520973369,29.2720403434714));
#565=CARTESIAN_POINT('',(-6.76368011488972,43.2477398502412,29.2277713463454));
#566=CARTESIAN_POINT('',(-6.85310995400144,43.0545364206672,29.2068797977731));
#567=CARTESIAN_POINT('',(-7.01528530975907,42.6610224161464,29.1683513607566));
#568=CARTESIAN_POINT('',(-7.08803748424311,42.4607147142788,29.1507131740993));
#569=CARTESIAN_POINT('',(-7.21623355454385,42.0545737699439,29.1192433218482));
#570=CARTESIAN_POINT('',(-7.27169537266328,41.8487464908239,29.1054077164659));
#571=CARTESIAN_POINT('',(-7.36491393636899,41.4329707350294,29.0819591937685));
#572=CARTESIAN_POINT('',(-7.402678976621,41.2230242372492,29.072344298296));
#573=CARTESIAN_POINT('',(-7.45426794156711,40.8441137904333,29.0591545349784));
#574=CARTESIAN_POINT('',(-7.47142252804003,40.6756242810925,29.0547430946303));
#575=CARTESIAN_POINT('',(-7.49428407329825,40.3380945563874,29.0488508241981));
#576=CARTESIAN_POINT('',(-7.50000955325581,40.1690556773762,29.0473652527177));
#577=CARTESIAN_POINT('',(-7.49999999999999,40.,29.0473750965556));
#578=B_SPLINE_CURVE_WITH_KNOTS('',3,(#500,#501,#502,#503,#504,#505,#506,#507,#508,#509,#510,
#511,#512,#513,#514,#515,#516,#517,#518,#519,#520,#521,#522,#523,#524,#525,#526,#527,#528,#529,
#530,#531,#532,#533,#534,#535,#536,#537,#538,#539,#540,#541,#542,#543,#544,#545,#546,#547,#548,
#549,#550,#551,#552,#553,#554,#555,#556,#557,#558,#559,#560,#561,#562,#563,#564,#565,#566,#567,
#568,#569,#570,#571,#572,#573,#574,#575,#576,#577),.UNSPECIFIED.,.F.,.F.,(4,2,2,2,2,2,2,2,2,2,2,
2,2,2,2,2,2,2,2,2,2,2,2,2,2,2,2,2,2,2,2,2,2,2,2,2,2,2,4),(0.,0.622023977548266,1.24394329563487,
1.86463397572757,2.48533319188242,3.10583766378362,3.72657265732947,4.34722749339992,
4.96811573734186,5.60101548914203,6.23413570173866,6.86725224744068,7.50036498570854,
8.14245446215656,8.78431031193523,9.42630689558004,10.0680386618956,10.6970193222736,
11.3257578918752,11.9545466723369,12.583327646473,13.198018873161,13.8129216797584,
14.4276174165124,15.0425433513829,15.662806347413,16.2832834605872,16.9037298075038,
17.5241884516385,18.1615007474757,18.7986020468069,19.4361154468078,20.0733827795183,
20.7143553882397,21.3550716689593,21.9951215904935,22.6348712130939,23.1427263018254,
23.6497577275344),.UNSPECIFIED.);
#579=CARTESIAN_POINT('',(7.49999999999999,40.,29.0473750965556));
#580=VERTEX_POINT('',#579);
#581=EDGE_CURVE('E84',#580,#497,#578,.T.);
#582=ORIENTED_EDGE('',*,*,#581,.F.);
#583=DIRECTION('',(0.,-1.,0.));
#584=VECTOR('',#583,1.);
#585=CARTESIAN_POINT('',(7.49999999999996,70.,29.0473750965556));
#586=LINE('',#585,#584);
#587=EDGE_CURVE('E50',#51,#580,#586,.F.);
#588=ORIENTED_EDGE('',*,*,#587,.F.);
#589=ORIENTED_EDGE('',*,*,#54,.F.);
#590=DIRECTION('',(0.,-1.,0.));
#591=VECTOR('',#590,1.);
#592=CARTESIAN_POINT('',(7.49999999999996,70.,-29.0473750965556));
#593=LINE('',#592,#591);
#594=CARTESIAN_POINT('',(7.49999999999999,40.,-29.0473750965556));
#595=VERTEX_POINT('',#594);
#596=EDGE_CURVE('E100',#595,#49,#593,.T.);
#597=ORIENTED_EDGE('',*,*,#596,.F.);
#598=CARTESIAN_POINT('',(-7.49999999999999,40.,-29.0473750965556));
#599=CARTESIAN_POINT('',(-7.50002630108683,40.2074094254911,-29.0473511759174));
#600=CARTESIAN_POINT('',(-7.49139743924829,40.4148104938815,-29.0495957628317));
#601=CARTESIAN_POINT('',(-7.45702283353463,40.8280617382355,-29.058447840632));
#602=CARTESIAN_POINT('',(-7.43127996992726,41.0339121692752,-29.0650545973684));
#603=CARTESIAN_POINT('',(-7.36293825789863,41.4421950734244,-29.0824398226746));
#604=CARTESIAN_POINT('',(-7.32037280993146,41.6446334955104,-29.0932100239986));
#605=CARTESIAN_POINT('',(-7.21874728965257,42.0450801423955,-29.1185927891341));
#606=CARTESIAN_POINT('',(-7.15968699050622,42.24308830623,-29.1332054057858));
#607=CARTESIAN_POINT('',(-7.02556473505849,42.6332457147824,-29.1658394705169));
#608=CARTESIAN_POINT('',(-6.95050780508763,42.8253967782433,-29.1838598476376));
#609=CARTESIAN_POINT('',(-6.78492631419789,43.2026916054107,-29.2227994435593));
#610=CARTESIAN_POINT('',(-6.69439601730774,43.3878327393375,-29.2437197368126));
#611=CARTESIAN_POINT('',(-6.49856054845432,43.7498067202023,-29.2878606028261));
#612=CARTESIAN_POINT('',(-6.3932572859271,43.9266406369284,-29.311080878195));
#613=CARTESIAN_POINT('',(-6.16855831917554,44.270968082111,-29.3591908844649));
#614=CARTESIAN_POINT('',(-6.04915733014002,44.4384580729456,-29.3840812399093));
#615=CARTESIAN_POINT('',(-5.79464941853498,44.7661199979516,-29.4353394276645));
#616=CARTESIAN_POINT('',(-5.65928334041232,44.9260876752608,-29.4617265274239));
#617=CARTESIAN_POINT('',(-5.37562488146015,45.2341682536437,-29.5148010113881));
#618=CARTESIAN_POINT('',(-5.22732801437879,45.3822770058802,-29.5414884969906));
#619=CARTESIAN_POINT('',(-4.91882000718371,45.6656042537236,-29.5944200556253));
#620=CARTESIAN_POINT('',(-4.75860893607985,45.8008228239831,-29.6206641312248));
#621=CARTESIAN_POINT('',(-4.42731474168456,46.0574572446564,-29.6719897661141));
#622=CARTESIAN_POINT('',(-4.25623168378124,46.1788731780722,-29.6970713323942));
#623=CARTESIAN_POINT('',(-3.90181138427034,46.4086739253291,-29.7457275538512));
#624=CARTESIAN_POINT('',(-3.71833478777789,46.5168495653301,-29.7692758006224));
#625=CARTESIAN_POINT('',(-3.34266809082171,46.7172820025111,-29.8137942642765));
#626=CARTESIAN_POINT('',(-3.15048118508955,46.8095445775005,-29.8347654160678));
#627=CARTESIAN_POINT('',(-2.7586331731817,46.9774916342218,-29.8735452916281));
#628=CARTESIAN_POINT('',(-2.55897043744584,47.053172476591,-29.8913533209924));
#629=CARTESIAN_POINT('',(-2.15373172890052,47.1872782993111,-29.9232806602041));
#630=CARTESIAN_POINT('',(-1.94815822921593,47.2457103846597,-29.9374014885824));
#631=CARTESIAN_POINT('',(-1.53667744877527,47.3438728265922,-29.9613124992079));
#632=CARTESIAN_POINT('',(-1.33085796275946,47.3839517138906,-29.9711831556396));
#633=CARTESIAN_POINT('',(-0.916507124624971,47.4467377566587,-29.986713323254));
#634=CARTESIAN_POINT('',(-0.707976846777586,47.4694515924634,-29.9923744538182));
#635=CARTESIAN_POINT('',(-0.289657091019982,47.4973358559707,-29.9993310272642));
#636=CARTESIAN_POINT('',(-0.0798675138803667,47.5025048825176,-30.0006261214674));
#637=CARTESIAN_POINT('',(0.33938668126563,47.4952499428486,-29.9988126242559));
#638=CARTESIAN_POINT('',(0.548851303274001,47.4828261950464,-29.9957040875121));
#639=CARTESIAN_POINT('',(0.961217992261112,47.4409706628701,-29.9852905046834));
#640=CARTESIAN_POINT('',(1.16416193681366,47.4119262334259,-29.9780810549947));
#641=CARTESIAN_POINT('',(1.56688998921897,47.3373569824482,-29.9597313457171));
#642=CARTESIAN_POINT('',(1.76667298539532,47.2918264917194,-29.9485897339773));
#643=CARTESIAN_POINT('',(2.16155863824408,47.184671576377,-29.9226804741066));
#644=CARTESIAN_POINT('',(2.35666284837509,47.1230525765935,-29.9079140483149));
#645=CARTESIAN_POINT('',(2.74101865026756,46.9841669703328,-29.8751407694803));
#646=CARTESIAN_POINT('',(2.93026802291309,46.9068945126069,-29.857132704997));
#647=CARTESIAN_POINT('',(3.30321049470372,46.7365562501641,-29.8181867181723));
#648=CARTESIAN_POINT('',(3.48684111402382,46.6433591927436,-29.7972247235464));
#649=CARTESIAN_POINT('',(3.84567797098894,46.4422880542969,-29.7530411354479));
#650=CARTESIAN_POINT('',(4.02088127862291,46.3344089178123,-29.7298187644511));
#651=CARTESIAN_POINT('',(4.3616758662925,46.1047524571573,-29.6817351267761));
#652=CARTESIAN_POINT('',(4.5272676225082,45.9829758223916,-29.6568739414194));
#653=CARTESIAN_POINT('',(4.84781396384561,45.7263301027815,-29.6061655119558));
#654=CARTESIAN_POINT('',(5.00276833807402,45.5914607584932,-29.580318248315));
#655=CARTESIAN_POINT('',(5.30512497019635,45.3056657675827,-29.5276114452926));
#656=CARTESIAN_POINT('',(5.45220775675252,45.1544034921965,-29.5007434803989));
#657=CARTESIAN_POINT('',(5.73309923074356,44.8400403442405,-29.4474448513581));
#658=CARTESIAN_POINT('',(5.86691229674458,44.676943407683,-29.4210140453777));
#659=CARTESIAN_POINT('',(6.12049046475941,44.3398284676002,-29.3693097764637));
#660=CARTESIAN_POINT('',(6.24024642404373,44.1658034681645,-29.3440370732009));
#661=CARTESIAN_POINT('',(6.46471718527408,43.8081478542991,-29.2954027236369));
#662=CARTESIAN_POINT('',(6.56943777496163,43.624520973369,-29.2720403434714));
#663=CARTESIAN_POINT('',(6.76368011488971,43.2477398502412,-29.2277713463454));
#664=CARTESIAN_POINT('',(6.85310995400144,43.0545364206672,-29.2068797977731));
#665=CARTESIAN_POINT('',(7.01528530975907,42.6610224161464,-29.1683513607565));
#666=CARTESIAN_POINT('',(7.08803748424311,42.4607147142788,-29.1507131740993));
#667=CARTESIAN_POINT('',(7.21623355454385,42.0545737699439,-29.1192433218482));
#668=CARTESIAN_POINT('',(7.27169537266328,41.8487464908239,-29.1054077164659));
#669=CARTESIAN_POINT('',(7.36491393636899,41.4329707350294,-29.0819591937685));
#670=CARTESIAN_POINT('',(7.402678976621,41.2230242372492,-29.072344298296));
#671=CARTESIAN_POINT('',(7.4542679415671,40.8441137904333,-29.0591545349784));
#672=CARTESIAN_POINT('',(7.47142252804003,40.6756242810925,-29.0547430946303));
#673=CARTESIAN_POINT('',(7.49428407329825,40.3380945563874,-29.0488508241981));
#674=CARTESIAN_POINT('',(7.50000955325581,40.1690556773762,-29.0473652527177));
#675=CARTESIAN_POINT('',(7.49999999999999,40.,-29.0473750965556));
#676=B_SPLINE_CURVE_WITH_KNOTS('',3,(#598,#599,#600,#601,#602,#603,#604,#605,#606,#607,#608,
#609,#610,#611,#612,#613,#614,#615,#616,#617,#618,#619,#620,#621,#622,#623,#624,#625,#626,#627,
#628,#629,#630,#631,#632,#633,#634,#635,#636,#637,#638,#639,#640,#641,#642,#643,#644,#645,#646,
#647,#648,#649,#650,#651,#652,#653,#654,#655,#656,#657,#658,#659,#660,#661,#662,#663,#664,#665,
#666,#667,#668,#669,#670,#671,#672,#673,#674,#675),.UNSPECIFIED.,.F.,.F.,(4,2,2,2,2,2,2,2,2,2,2,
2,2,2,2,2,2,2,2,2,2,2,2,2,2,2,2,2,2,2,2,2,2,2,2,2,2,2,4),(0.,0.622023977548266,1.24394329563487,
1.86463397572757,2.48533319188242,3.10583766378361,3.72657265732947,4.34722749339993,
4.96811573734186,5.60101548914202,6.23413570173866,6.86725224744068,7.50036498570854,
8.14245446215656,8.78431031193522,9.42630689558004,10.0680386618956,10.6970193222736,
11.3257578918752,11.9545466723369,12.583327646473,13.198018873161,13.8129216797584,
14.4276174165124,15.0425433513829,15.662806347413,16.2832834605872,16.9037298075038,
17.5241884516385,18.1615007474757,18.7986020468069,19.4361154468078,20.0733827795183,
20.7143553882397,21.3550716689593,21.9951215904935,22.6348712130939,23.1427263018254,
23.6497577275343),.UNSPECIFIED.);
#677=EDGE_CURVE('E103',#488,#595,#676,.T.);
#678=ORIENTED_EDGE('',*,*,#677,.F.);
#679=EDGE_LOOP('',(#490,#491,#499,#582,#588,#589,#597,#678));
#680=FACE_BOUND('',#679,.T.);
#681=ORIENTED_EDGE('',*,*,#151,.T.);
#682=EDGE_LOOP('',(#681));
#683=FACE_BOUND('',#682,.T.);
#684=ADVANCED_FACE('F86',(#321,#482,#680,#683),#160,.T.);
#685=CARTESIAN_POINT('',(-7.5,0.,-30.));
#686=DIRECTION('',(-1.,0.,0.));
#687=DIRECTION('',(0.,0.,1.));
#688=AXIS2_PLACEMENT_3D('',#685,#686,#687);
#689=PLANE('',#688);
#690=CARTESIAN_POINT('',(-7.5,25.,0.));
#691=DIRECTION('',(-1.,0.,0.));
#692=DIRECTION('',(0.,0.,1.));
#693=AXIS2_PLACEMENT_3D('',#690,#691,#692);
#694=CIRCLE('',#693,10.);
#695=CARTESIAN_POINT('',(-7.5,25.,10.));
#696=VERTEX_POINT('',#695);
#697=EDGE_CURVE('E179',#696,#696,#694,.T.);
#698=ORIENTED_EDGE('',*,*,#697,.T.);
#699=EDGE_LOOP('',(#698));
#700=FACE_BOUND('',#699,.T.);
#701=ORIENTED_EDGE('',*,*,#489,.T.);
#702=DIRECTION('',(0.,0.,1.));
#703=VECTOR('',#702,1.);
#704=CARTESIAN_POINT('',(-7.5,40.,-30.));
#705=LINE('',#704,#703);
#706=EDGE_CURVE('E106',#488,#497,#705,.T.);
#707=ORIENTED_EDGE('',*,*,#706,.T.);
#708=ORIENTED_EDGE('',*,*,#498,.T.);
#709=ORIENTED_EDGE('',*,*,#32,.F.);
#710=EDGE_LOOP('',(#701,#707,#708,#709));
#711=FACE_BOUND('',#710,.T.);
#712=ADVANCED_FACE('F154',(#700,#711),#689,.F.);
#713=CARTESIAN_POINT('',(0.,40.,-30.));
#714=DIRECTION('',(0.,0.,1.));
#715=DIRECTION('',(1.,0.,0.));
#716=AXIS2_PLACEMENT_3D('',#713,#714,#715);
#717=CYLINDRICAL_SURFACE('',#716,7.49999999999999);
#718=ORIENTED_EDGE('',*,*,#706,.F.);
#719=ORIENTED_EDGE('',*,*,#677,.T.);
#720=DIRECTION('',(0.,0.,1.));
#721=VECTOR('',#720,1.);
#722=CARTESIAN_POINT('',(7.49999999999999,40.,-30.));
#723=LINE('',#722,#721);
#724=EDGE_CURVE('E57',#595,#580,#723,.T.);
#725=ORIENTED_EDGE('',*,*,#724,.T.);
#726=ORIENTED_EDGE('',*,*,#581,.T.);
#727=EDGE_LOOP('',(#718,#719,#725,#726));
#728=FACE_BOUND('',#727,.T.);
#729=ADVANCED_FACE('F102',(#728),#717,.F.);
#730=CARTESIAN_POINT('',(7.49999999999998,40.,-30.));
#731=DIRECTION('',(1.,0.,0.));
#732=DIRECTION('',(0.,1.,0.));
#733=AXIS2_PLACEMENT_3D('',#730,#731,#732);
#734=PLANE('',#733);
#735=CARTESIAN_POINT('',(7.49999999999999,25.,0.));
#736=DIRECTION('',(1.,0.,0.));
#737=DIRECTION('',(0.,1.,0.));
#738=AXIS2_PLACEMENT_3D('',#735,#736,#737);
#739=CIRCLE('',#738,10.);
#740=CARTESIAN_POINT('',(7.49999999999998,35.,0.));
#741=VERTEX_POINT('',#740);
#742=EDGE_CURVE('E44',#741,#741,#739,.T.);
#743=ORIENTED_EDGE('',*,*,#742,.T.);
#744=EDGE_LOOP('',(#743));
#745=FACE_BOUND('',#744,.T.);
#746=ORIENTED_EDGE('',*,*,#587,.T.);
#747=ORIENTED_EDGE('',*,*,#724,.F.);
#748=ORIENTED_EDGE('',*,*,#596,.T.);
#749=ORIENTED_EDGE('',*,*,#52,.T.);
#750=EDGE_LOOP('',(#746,#747,#748,#749));
#751=FACE_BOUND('',#750,.T.);
#752=ADVANCED_FACE('F96',(#745,#751),#734,.F.);
#753=CARTESIAN_POINT('',(-30.,25.,0.));
#754=DIRECTION('',(1.,0.,0.));
#755=DIRECTION('',(0.,0.,-1.));
#756=AXIS2_PLACEMENT_3D('',#753,#754,#755);
#757=CYLINDRICAL_SURFACE('',#756,10.);
#758=ORIENTED_EDGE('',*,*,#479,.T.);
#759=EDGE_LOOP('',(#758));
#760=FACE_BOUND('',#759,.T.);
#761=ORIENTED_EDGE('',*,*,#742,.F.);
#762=EDGE_LOOP('',(#761));
#763=FACE_BOUND('',#762,.T.);
#764=ADVANCED_FACE('F192',(#760,#763),#757,.F.);
#765=ORIENTED_EDGE('',*,*,#318,.T.);
#766=EDGE_LOOP('',(#765));
#767=FACE_BOUND('',#766,.T.);
#768=ORIENTED_EDGE('',*,*,#697,.F.);
#769=EDGE_LOOP('',(#768));
#770=FACE_BOUND('',#769,.T.);
#771=ADVANCED_FACE('F194',(#767,#770),#757,.F.);
#772=CLOSED_SHELL('',(#43,#58,#75,#95,#115,#135,#155,#684,#712,#729,#752,#764,#771));
#773=MANIFOLD_SOLID_BREP('B2',#772);
#774=ADVANCED_BREP_SHAPE_REPRESENTATION('',(#18,#773),#14);
#775=SHAPE_DEFINITION_REPRESENTATION(#9,#774);
ENDSEC;
END-ISO-10303-21;
